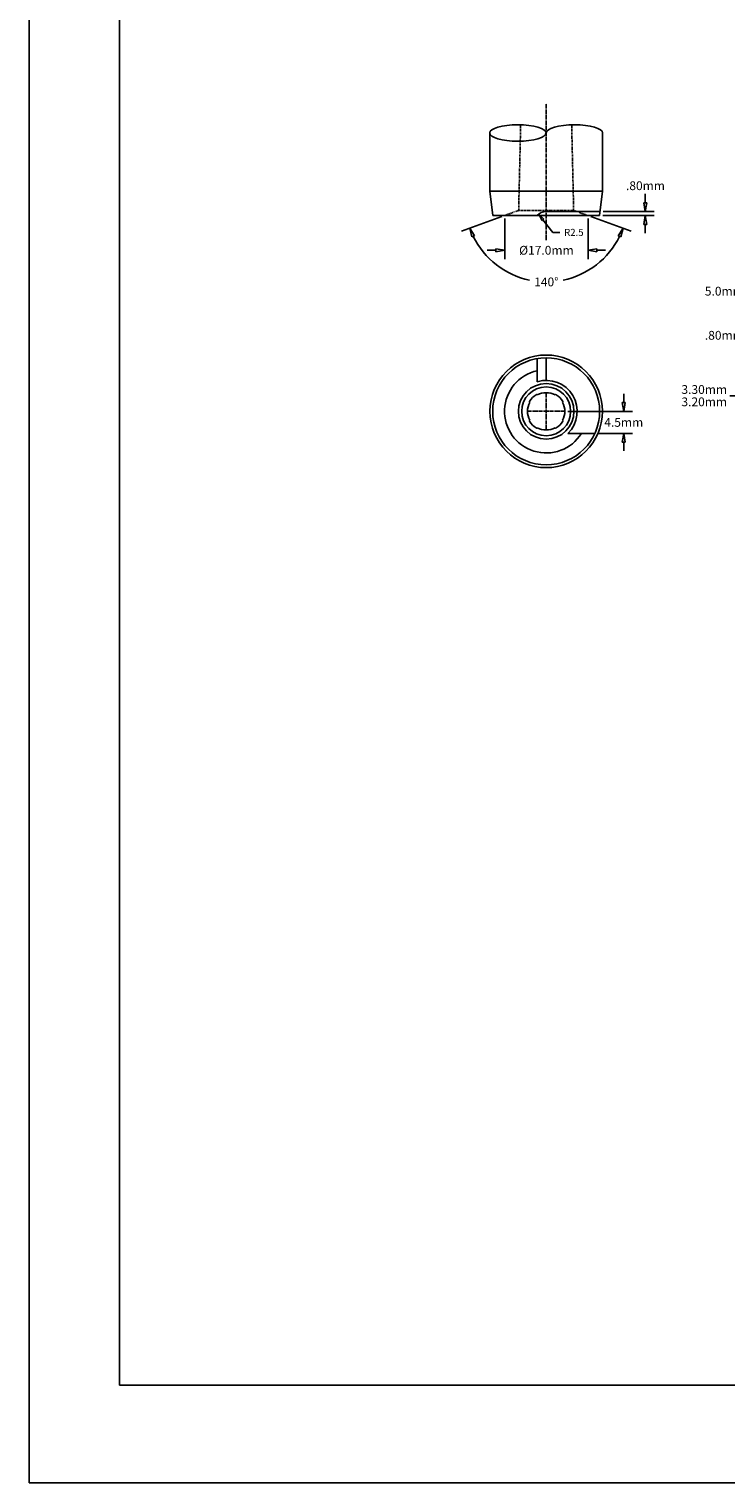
# Model space of a CAD drawing. Units: inches. Extents: x 0 to 841, y 0 to 594.
# Drawn here: x 0 to 142, y 0 to 297 of the extents above; entities that cross this region are included whole.
import ezdxf

# ---------------------------------------------------------------- set-up
doc = ezdxf.new("R2010")
doc.units = ezdxf.units.IN
doc.header["$MEASUREMENT"] = 0
doc.linetypes.add('CENTER2', pattern=[1.125, 0.75, -0.125, 0.125, -0.125])
doc.linetypes.add('HIDDEN2', pattern=[0.1875, 0.125, -0.0625])
doc.layers.add('CENTERLINE', color=1, linetype='CENTER2')
doc.layers.add('HIDDEN', color=5, linetype='HIDDEN2')
doc.dimstyles.get("Standard").update_dxf_attribs({"dimscale": 10, "dimtxt": 0.18, "dimasz": 0.18, "dimexe": 0.18, "dimexo": 0.0625, "dimgap": 0.09, "dimtad": 0, "dimtih": 1, "dimtoh": 1, "dimdec": 4, "dimzin": 0, "dimdsep": 46, "dimtxsty": 'Standard', "dimblk": 'CLOSEDBLANK', "dimcen": 0.09, "dimadec": 4, "dimazin": 0, "dimtfac": 1, "dimtdec": 4, "dimtofl": 0, "dimtmove": 0, "dimatfit": 3, "dimldrblk": 'CLOSEDBLANK', "dimfxl": 0, "dimtolj": 1, "dimtzin": 0, "dimarcsym": 0})
doc.dimstyles.new('Standard$0', dxfattribs={"dimscale": 10, "dimtxt": 0.18, "dimasz": 0.18, "dimexe": 0.18, "dimexo": 0.0625, "dimgap": 0.09, "dimtad": 0, "dimtih": 1, "dimtoh": 1, "dimdec": 4, "dimzin": 4, "dimdsep": 46, "dimtxsty": 'Standard', "dimblk": 'CLOSEDBLANK', "dimcen": 0.09, "dimadec": 5, "dimazin": 1, "dimtfac": 1, "dimtdec": 4, "dimtofl": 0, "dimtmove": 0, "dimatfit": 3, "dimldrblk": 'CLOSEDBLANK', "dimfxl": 0, "dimtolj": 1, "dimtzin": 0, "dimarcsym": 0})

# ---------------------------------------------------------------- blocks, each defined once
blk = doc.blocks.new('_ClosedBlank')
at = {"color": 0, "linetype": 'ByBlock', "lineweight": -2}
for p, q in [((-1, 0.17), (0, 0)), ((-1, 0.17), (-1, -0.17)), ((0, 0), (-1, -0.17))]:
    blk.add_line(p, q, dxfattribs=at)
blk = doc.blocks.new('*D7')
at = {"color": 0, "lineweight": -2}
for p, q in [((150, 230.46), (150, 245.26)), ((155, 231.1), (155, 245.26)), ((148.2, 243.46), (146.4, 243.46)), ((156.8, 243.46), (158.6, 243.46))]:
    blk.add_line(p, q, dxfattribs=at)
at = {"layer": 'Defpoints', "color": 0}
for p in [(155, 243.46), (150, 229.83), (155, 230.48)]:
    blk.add_point(p, dxfattribs=at)
at = {"color": 0, "lineweight": -2, "xscale": 1.8, "yscale": 1.8, "zscale": 1.8}
blk.add_blockref('_ClosedBlank', (150, 243.46), dxfattribs=at)
at = {"color": 0, "lineweight": -2, "xscale": 1.8, "yscale": 1.8, "zscale": 1.8, "rotation": 180}
blk.add_blockref('_ClosedBlank', (155, 243.46), dxfattribs=at)
at = {"color": 0, "insert": (142.05, 243.46), "char_height": 1.8, "attachment_point": 5}
blk.add_mtext('\\A1;5.0mm', dxfattribs=at)
blk = doc.blocks.new('*D23')
at = {"color": 0, "lineweight": -2}
for p, q in [((121.5, 220.71), (121.5, 222.51)), ((110.08, 218.91), (123.3, 218.91)), ((116.23, 214.41), (123.3, 214.41)), ((121.5, 212.61), (121.5, 210.81))]:
    blk.add_line(p, q, dxfattribs=at)
at = {"layer": 'Defpoints', "color": 0}
for p in [(109.46, 218.91), (121.5, 218.91), (115.6, 214.41)]:
    blk.add_point(p, dxfattribs=at)
at = {"color": 0, "lineweight": -2, "xscale": 1.8, "yscale": 1.8, "zscale": 1.8}
for p, rotation in [((121.5, 218.91), 270), ((121.5, 214.41), 90)]:
    blk.add_blockref('_ClosedBlank', p, dxfattribs=dict(at, rotation=rotation))
at = {"color": 0, "insert": (121.5, 216.66), "char_height": 1.8, "attachment_point": 5}
blk.add_mtext('\\A1;4.5mm', dxfattribs=at)
blk = doc.blocks.new('*D24')
at = {"color": 0, "lineweight": -2}
for p, q in [((106.99, 255.47), (105, 258.05)), ((108.43, 255.47), (106.99, 255.47))]:
    blk.add_line(p, q, dxfattribs=at)
at = {"layer": 'Defpoints', "color": 0}
for p in [(104.12, 259.19), (105.65, 257.21)]:
    blk.add_point(p, dxfattribs=at)
at = {"color": 0, "lineweight": -2, "xscale": 1.44, "yscale": 1.44, "zscale": 1.44, "rotation": 127.7379653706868}
blk.add_blockref('_ClosedBlank', (104.12, 259.19), dxfattribs=at)
at = {"color": 0, "insert": (111.31, 255.47), "char_height": 1.44, "attachment_point": 5}
blk.add_mtext('\\A1;R2.5', dxfattribs=at)
blk = doc.blocks.new('*D25')
at = {"color": 0, "lineweight": -2}
for p, q in [((150, 230.46), (150, 236.24)), ((150.8, 230.34), (150.8, 236.24)), ((148.2, 234.44), (146.4, 234.44)), ((152.6, 234.44), (154.4, 234.44))]:
    blk.add_line(p, q, dxfattribs=at)
at = {"layer": 'Defpoints', "color": 0}
for p in [(150.8, 234.44), (150, 229.83), (150.8, 229.71)]:
    blk.add_point(p, dxfattribs=at)
at = {"color": 0, "lineweight": -2, "xscale": 1.8, "yscale": 1.8, "zscale": 1.8}
blk.add_blockref('_ClosedBlank', (150, 234.44), dxfattribs=at)
at = {"color": 0, "lineweight": -2, "xscale": 1.8, "yscale": 1.8, "zscale": 1.8, "rotation": 180}
blk.add_blockref('_ClosedBlank', (150.8, 234.44), dxfattribs=at)
at = {"color": 0, "insert": (142.05, 234.44), "char_height": 1.8, "attachment_point": 5}
blk.add_mtext('\\A1;.80mm', dxfattribs=at)
blk = doc.blocks.new('*D32')
at = {"color": 0, "lineweight": -2}
for p, q in [((96.61, 258.7), (88.36, 255.69)), ((114.79, 258.7), (123.04, 255.69))]:
    blk.add_line(p, q, dxfattribs=at)
for start, end in [(206.197, 258.0416), (281.9584, 333.803)]:
    blk.add_arc((105.7, 262), 16.65, start, end, dxfattribs=at)
at = {"layer": 'Defpoints', "color": 0}
for p in [(97.2, 258.91), (100.03, 259.94), (111.37, 259.94), (114.2, 258.91), (99.1, 246.72)]:
    blk.add_point(p, dxfattribs=at)
at = {"color": 0, "lineweight": -2, "xscale": 1.8, "yscale": 1.8, "zscale": 1.8}
for p, rotation in [((90.05, 256.31), 113.0985010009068), ((121.35, 256.31), 66.90149899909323)]:
    blk.add_blockref('_ClosedBlank', p, dxfattribs=dict(at, rotation=rotation))
at = {"color": 0, "insert": (105.7, 245.35), "char_height": 1.8, "attachment_point": 5}
blk.add_mtext('\\A1;140°', dxfattribs=at)
blk = doc.blocks.new('*D33')
at = {"color": 0, "lineweight": -2}
for p, q in [((97.2, 258.29), (97.2, 250.01)), ((114.2, 258.29), (114.2, 250.01)), ((95.4, 251.81), (93.6, 251.81)), ((116, 251.81), (117.8, 251.81))]:
    blk.add_line(p, q, dxfattribs=at)
at = {"layer": 'Defpoints', "color": 0}
for p in [(97.2, 258.91), (114.2, 258.91), (114.2, 251.81)]:
    blk.add_point(p, dxfattribs=at)
at = {"color": 0, "lineweight": -2, "xscale": 1.8, "yscale": 1.8, "zscale": 1.8}
blk.add_blockref('_ClosedBlank', (97.2, 251.81), dxfattribs=at)
at = {"color": 0, "lineweight": -2, "xscale": 1.8, "yscale": 1.8, "zscale": 1.8, "rotation": 180}
blk.add_blockref('_ClosedBlank', (114.2, 251.81), dxfattribs=at)
at = {"color": 0, "insert": (105.7, 251.81), "char_height": 1.8, "attachment_point": 5}
blk.add_mtext('\\A1;%%C17.0mm', dxfattribs=at)
blk = doc.blocks.new('*D34')
at = {"color": 0, "lineweight": -2}
for p, q in [((150, 229.21), (150, 220.31)), ((146.8, 220.04), (146.8, 223.91)), ((145, 222.11), (143.2, 222.11)), ((151.8, 222.11), (153.6, 222.11))]:
    blk.add_line(p, q, dxfattribs=at)
at = {"layer": 'Defpoints', "color": 0}
for p in [(150, 229.83), (150, 222.11), (146.8, 219.41)]:
    blk.add_point(p, dxfattribs=at)
at = {"color": 0, "lineweight": -2, "xscale": 1.8, "yscale": 1.8, "zscale": 1.8}
blk.add_blockref('_ClosedBlank', (146.8, 222.11), dxfattribs=at)
at = {"color": 0, "lineweight": -2, "xscale": 1.8, "yscale": 1.8, "zscale": 1.8, "rotation": 180}
blk.add_blockref('_ClosedBlank', (150, 222.11), dxfattribs=at)
at = {"color": 0, "insert": (137.95, 222.11), "char_height": 1.8, "attachment_point": 5}
blk.add_mtext('\\A1;\\S3.30mm^ 3.20mm;', dxfattribs=at)
blk = doc.blocks.new('*D35')
at = {"color": 0, "lineweight": -2}
for p, q in [((125.91, 261.51), (125.91, 263.31)), ((117.2, 258.91), (127.71, 258.91)), ((117.29, 259.71), (127.71, 259.71)), ((125.91, 257.11), (125.91, 255.31))]:
    blk.add_line(p, q, dxfattribs=at)
at = {"layer": 'Defpoints', "color": 0}
for p in [(116.57, 258.91), (116.67, 259.71), (125.91, 259.71)]:
    blk.add_point(p, dxfattribs=at)
at = {"color": 0, "lineweight": -2, "xscale": 1.8, "yscale": 1.8, "zscale": 1.8}
for p, rotation in [((125.91, 259.71), 270), ((125.91, 258.91), 90)]:
    blk.add_blockref('_ClosedBlank', p, dxfattribs=dict(at, rotation=rotation))
at = {"color": 0, "insert": (125.94, 265), "char_height": 1.8, "attachment_point": 5}
blk.add_mtext('\\A1;.80mm', dxfattribs=at)

msp = doc.modelspace()

# ---------------------------------------------------------------- linework, layer by layer
for p, q in [((94.11497, 263.9106), (94.11497, 275.77746)), ((117.18497, 263.9106), (117.18497, 275.77746)), ((117.18497, 263.9106), (94.11497, 263.9106)), ((94.72889, 258.9106), (94.11497, 263.9106)), ((116.57104, 258.9106), (117.18497, 263.9106)), ((116.57104, 258.9106), (94.72889, 258.9106)), ((116.66927, 259.7106), (105.64997, 259.7106)), ((103.81693, 224.97022), (103.81693, 229.67919)), ((105.64997, 225.2414), (105.64997, 229.8317)), ((110.10294, 214.4106), (115.60087, 214.4106))]:
    msp.add_line(p, q)
for points in [[(0, 0), (841, 0), (841, 594), (0, 594)], [(18.5, 20), (822.5, 20), (822.5, 574), (18.5, 574)]]:
    msp.add_lwpolyline(points, close=True)
for radius in [11.5, 10.92349, 5.67115, 5]:
    msp.add_circle((105.64997, 218.9106), radius)
for centre, radius, start, end in [((105.64997, 257.2106), 2.5, 90, 137.156357), ((105.64997, 218.9106), 8.5, 102.4537006, 328.0342812), ((105.64997, 218.9106), 6.3308, 314.6990904, 106.8305173)]:
    msp.add_arc(centre, radius, start, end)
at = {"ltscale": 0.25}
for centre, radius, start, end in [((105.64997, 218.9106), 3.81, 151.3407406, 208.6592594), ((102.3825, 220.87014), 0.1524, 149.0482979, 240.1945192), ((105.64997, 218.9106), 3.9624, 120.9517021, 149.0482979), ((103.69042, 222.17806), 0.1524, 29.8054808, 120.9517021), ((105.64997, 218.9106), 3.81, 61.3407406, 118.6592594), ((107.60951, 222.17806), 0.1524, 59.0482979, 150.1945192), ((105.64997, 218.9106), 3.9624, 30.9517021, 59.0482979), ((108.91743, 220.87014), 0.1524, 299.8054808, 30.9517021), ((105.64997, 218.9106), 3.81, 331.3407406, 28.6592594), ((102.3825, 216.95106), 0.1524, 119.8054808, 210.9517021), ((105.64997, 218.9106), 3.9624, 210.9517021, 239.0482979), ((105.64997, 218.9106), 3.9624, 300.9517021, 329.0482979), ((108.91743, 216.95106), 0.1524, 329.0482979, 60.1945192), ((103.69042, 215.64314), 0.1524, 239.0482979, 330.1945192), ((105.64997, 218.9106), 3.81, 241.3407406, 298.6592594), ((107.60951, 215.64314), 0.1524, 209.8054808, 300.9517021)]:
    msp.add_arc(centre, radius, start, end, dxfattribs=at)
msp.add_ellipse((99.88247, 275.77746), major_axis=(-5.7675, 0), ratio=0.291449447)
msp.add_ellipse((111.41747, 275.77746), major_axis=(-5.7675, 0), ratio=0.291449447, start_param=3.141592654, end_param=6.283185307)
at = {"layer": 'CENTERLINE'}
for p, q in [((105.64997, 253.9106), (105.64997, 281.80785)), ((105.64997, 215.1006), (105.64997, 222.7206)), ((101.83997, 218.9106), (109.45997, 218.9106))]:
    msp.add_line(p, q, dxfattribs=at)
at = {"layer": 'HIDDEN'}
for p, q in [((100.02852, 259.94021), (100.43902, 277.45055)), ((111.27141, 259.94021), (110.86091, 277.45055)), ((99.97879, 259.94021), (97.14997, 258.9106)), ((111.32114, 259.94021), (99.97879, 259.94021)), ((111.32114, 259.94021), (114.14997, 258.9106))]:
    msp.add_line(p, q, dxfattribs=at)

# ---------------------------------------------------------------- dimensions: what is measured, and where the dimension line sits
dim = msp.add_linear_dim(base=(125.90624, 259.7106), p1=(116.57104, 258.9106), p2=(116.66927, 259.7106), angle=90, dimstyle='Standard$0', override={"dimdec": 2, "dimpost": 'mm', "dimblk1": 'ClosedBlank', "dimblk2": 'ClosedBlank', "dimsah": 1, "dimtmove": 2})
dim.commit()
dim.dimension.update_dxf_attribs({"geometry": '*D35', "text_midpoint": (125.94037, 265.00227), "dimtype": 160})
dim = msp.add_angular_dim_2l(base=(99.1048, 246.71566), line1=((111.37087, 259.94021), (114.1997, 258.9106)), line2=((100.02852, 259.94021), (97.1997, 258.9106)), dimstyle='Standard', override={"dimadec": 0})
dim.commit()
dim.dimension.update_dxf_attribs({"geometry": '*D32', "text_midpoint": (105.6997, 245.35392)})
dim = msp.add_linear_dim(base=(114.1997, 251.81332), p1=(97.1997, 258.9106), p2=(114.1997, 258.9106), text='%%C<>', dimstyle='Standard$0', override={"dimdec": 1, "dimpost": 'mm'})
dim.commit()
dim.dimension.update_dxf_attribs({"geometry": '*D33', "text_midpoint": (105.6997, 251.81332)})
dim = msp.add_radius_dim(center=(105.64997, 257.2106), mpoint=(104.11984, 259.18764), dimstyle='Standard', override={"dimscale": 8, "dimdec": 1, "dimtmove": 1})
dim.commit()
dim.dimension.update_dxf_attribs({"geometry": '*D24', "text_midpoint": (106.99376, 255.47431), "dimtype": 164})
for base, p1, p2, override, picture, middle in [((154.99997, 243.46019), (149.99997, 229.83168), (154.99997, 230.4756), {"dimscale": 10, "dimdec": 1, "dimpost": 'mm', "dimblk1": 'ClosedBlank', "dimblk2": 'ClosedBlank', "dimsah": 1}, '*D7', (142.04997, 243.46019)), ((150.79997, 234.4356), (149.99997, 229.83168), (150.79997, 229.71386), {"dimscale": 10, "dimdec": 2, "dimpost": 'mm', "dimblk1": 'ClosedBlank', "dimblk2": 'ClosedBlank', "dimsah": 1}, '*D25', (142.04997, 234.4356)), ((149.99997, 222.11187), (146.79997, 219.4106), (149.99997, 229.83168), {"dimgap": 0.09, "dimdec": 2, "dimpost": 'mm', "dimtol": 0, "dimlim": 1, "dimtp": 0.1, "dimtm": 1e-09, "dimtdec": 2}, '*D34', (137.94997, 222.11187))]:
    dim = msp.add_linear_dim(base=base, p1=p1, p2=p2, dimstyle='Standard$0', override=override)
    dim.commit()
    dim.dimension.update_dxf_attribs({"geometry": picture, "text_midpoint": middle, "dimtype": 160})
dim = msp.add_linear_dim(base=(121.49722, 218.9106), p1=(115.60087, 214.4106), p2=(109.45997, 218.9106), angle=90, dimstyle='Standard$0', override={"dimdec": 1, "dimpost": 'mm'})
dim.commit()
dim.dimension.update_dxf_attribs({"geometry": '*D23', "text_midpoint": (121.49722, 216.6606)})

doc.saveas('drawing.dxf')
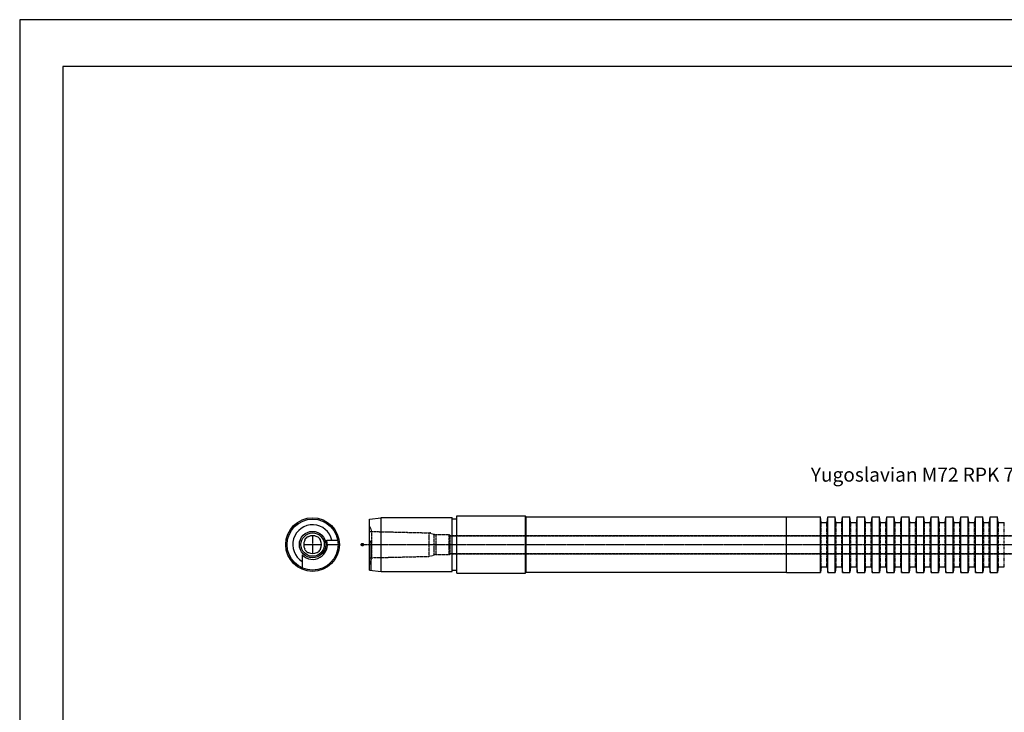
# Model space of a CAD drawing. Units: inches. Extents: x 0 to 841, y 0 to 594.
# Drawn here: x 0 to 422, y 297 to 594 of the extents above; entities that cross this region are included whole.
import ezdxf
from ezdxf.enums import TextEntityAlignment as Align

# ---------------------------------------------------------------- set-up
doc = ezdxf.new("R2010")
doc.units = ezdxf.units.IN
doc.header["$MEASUREMENT"] = 0
for name, pattern in [('CENTER2', [1.125, 0.75, -0.125, 0.125, -0.125]), ('HIDDEN2', [0.1875, 0.125, -0.0625]), ('PHANTOM', [2.5, 1.25, -0.25, 0.25, -0.25, 0.25, -0.25])]:
    doc.linetypes.add(name, pattern=pattern)
for name, color, linetype in [('CENTER', 1, 'CENTER2'), ('CENTERLINE', 1, 'CENTER2'), ('HIDDEN', 5, 'HIDDEN2'), ('PHANTOM', 252, 'PHANTOM')]:
    doc.layers.add(name, color=color, linetype=linetype)

msp = doc.modelspace()

# ---------------------------------------------------------------- hatches: boundary and pattern name
at = {"layer": 'CENTER'}
h = msp.add_hatch(dxfattribs=at)
h.set_pattern_fill('ANSI31', color=256, style=0)
h.set_pattern_definition([(45, (98, 318.91057), (-0.08838835, 0.08838835), [])])
h.paths.add_polyline_path([(146.99997, 369.4106, 0.414213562), (146.49997, 368.9106), (146.99997, 368.9106)])
h.paths.add_polyline_path([(147.49997, 368.9106), (146.99997, 368.9106), (146.99997, 368.4106, 0.414213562)])

# ---------------------------------------------------------------- linework, layer by layer
for p, q in [((149.99997, 379.83168), (154.99997, 380.4456)), ((149.99997, 379.83168), (154.99997, 380.4456)), ((154.99997, 380.4756), (185.49997, 380.4756)), ((154.99997, 357.3456), (154.99997, 380.4756)), ((185.49997, 357.3456), (185.49997, 380.4756)), ((187.49997, 356.6356), (187.49997, 381.1856)), ((187.49997, 381.1856), (216.99997, 381.1856)), ((216.99997, 356.6356), (216.99997, 381.1856)), ((217.24997, 357.0106), (217.24997, 380.8106)), ((217.24997, 380.7606), (328.99997, 380.7606)), ((328.99997, 380.8106), (343.49997, 380.8106)), ((328.99997, 357.0106), (328.99997, 380.8106)), ((343.49997, 357.0106), (343.49997, 380.8106)), ((343.78387, 378.49841), (343.49997, 380.8106)), ((346.38273, 378.49841), (346.66663, 380.8106)), ((346.66663, 357.0106), (346.66663, 380.8106)), ((346.66663, 380.8106), (349.8333, 380.8106)), ((349.8333, 357.0106), (349.8333, 380.8106)), ((350.1172, 378.49841), (349.8333, 380.8106)), ((352.71606, 378.49841), (352.99997, 380.8106)), ((352.99997, 357.0106), (352.99997, 380.8106)), ((352.99997, 380.8106), (356.16663, 380.8106)), ((356.16663, 357.0106), (356.16663, 380.8106)), ((356.45053, 378.49841), (356.16663, 380.8106)), ((359.0494, 378.49841), (359.3333, 380.8106)), ((359.3333, 357.0106), (359.3333, 380.8106)), ((359.3333, 380.8106), (362.49997, 380.8106)), ((362.49997, 357.0106), (362.49997, 380.8106)), ((362.78387, 378.49841), (362.49997, 380.8106)), ((365.38273, 378.49841), (365.66663, 380.8106)), ((365.66663, 357.0106), (365.66663, 380.8106)), ((365.66663, 380.8106), (368.8333, 380.8106)), ((368.8333, 357.0106), (368.8333, 380.8106)), ((369.1172, 378.49841), (368.8333, 380.8106)), ((371.71606, 378.49841), (371.99997, 380.8106)), ((371.99997, 357.0106), (371.99997, 380.8106)), ((371.99997, 380.8106), (375.16663, 380.8106)), ((375.16663, 357.0106), (375.16663, 380.8106)), ((375.45053, 378.49841), (375.16663, 380.8106)), ((378.0494, 378.49841), (378.3333, 380.8106)), ((378.3333, 357.0106), (378.3333, 380.8106)), ((378.3333, 380.8106), (381.49997, 380.8106)), ((381.49997, 357.0106), (381.49997, 380.8106)), ((381.78387, 378.49841), (381.49997, 380.8106)), ((384.38273, 378.49841), (384.66663, 380.8106)), ((384.66663, 357.0106), (384.66663, 380.8106)), ((384.66663, 380.8106), (387.8333, 380.8106)), ((387.8333, 357.0106), (387.8333, 380.8106)), ((388.1172, 378.49841), (387.8333, 380.8106)), ((390.71606, 378.49841), (390.99997, 380.8106)), ((390.99997, 357.0106), (390.99997, 380.8106)), ((390.99997, 380.8106), (394.16663, 380.8106)), ((394.16663, 357.0106), (394.16663, 380.8106)), ((394.45053, 378.49841), (394.16663, 380.8106)), ((397.0494, 378.49841), (397.3333, 380.8106)), ((397.3333, 357.0106), (397.3333, 380.8106)), ((397.3333, 380.8106), (400.49997, 380.8106)), ((400.49997, 357.0106), (400.49997, 380.8106)), ((400.78387, 378.49841), (400.49997, 380.8106)), ((403.38273, 378.49841), (403.66663, 380.8106)), ((403.66663, 357.0106), (403.66663, 380.8106)), ((403.66663, 380.8106), (406.8333, 380.8106)), ((406.8333, 357.0106), (406.8333, 380.8106)), ((407.1172, 378.49841), (406.8333, 380.8106)), ((409.71606, 378.49841), (409.99997, 380.8106)), ((409.99997, 357.0106), (409.99997, 380.8106)), ((409.99997, 380.8106), (413.16663, 380.8106)), ((413.16663, 357.0106), (413.16663, 380.8106)), ((413.45053, 378.49841), (413.16663, 380.8106)), ((416.0494, 378.49841), (416.3333, 380.8106)), ((416.3333, 357.0106), (416.3333, 380.8106)), ((416.3333, 380.8106), (419.49997, 380.8106)), ((419.49997, 357.0106), (419.49997, 380.8106)), ((419.78387, 378.49841), (419.49997, 380.8106)), ((149.99997, 357.98952), (149.99997, 379.83168)), ((185.49997, 379.9106), (187.49997, 379.9106)), ((343.88312, 378.4106), (346.28348, 378.4106)), ((350.21645, 378.4106), (352.61681, 378.4106)), ((356.54979, 378.4106), (358.95014, 378.4106)), ((362.88312, 378.4106), (365.28348, 378.4106)), ((369.21645, 378.4106), (371.61681, 378.4106)), ((375.54979, 378.4106), (377.95014, 378.4106)), ((381.88312, 378.4106), (384.28348, 378.4106)), ((388.21645, 378.4106), (390.70014, 378.4106)), ((394.54979, 378.4106), (396.95014, 378.4106)), ((400.88312, 378.4106), (403.36681, 378.4106)), ((407.21645, 378.4106), (409.61681, 378.4106)), ((413.54979, 378.4106), (415.95014, 378.4106)), ((419.88312, 378.4106), (422.28348, 378.4106)), ((131.70959, 370.74363), (136.41856, 370.74363)), ((131.98077, 368.9106), (136.57107, 368.9106)), ((150.79997, 357.89129), (150.79997, 368.9106)), ((121.14997, 364.45762), (121.14997, 358.95969)), ((343.78387, 359.32279), (343.49997, 357.0106)), ((343.88312, 359.4106), (346.28348, 359.4106)), ((346.38273, 359.32279), (346.66663, 357.0106)), ((350.1172, 359.32279), (349.8333, 357.0106)), ((350.13312, 359.4106), (352.61681, 359.4106)), ((352.71606, 359.32279), (352.99997, 357.0106)), ((356.45053, 359.32279), (356.16663, 357.0106)), ((356.54979, 359.4106), (358.95014, 359.4106)), ((359.0494, 359.32279), (359.3333, 357.0106)), ((362.78387, 359.32279), (362.49997, 357.0106)), ((362.88312, 359.4106), (365.28348, 359.4106)), ((365.38273, 359.32279), (365.66663, 357.0106)), ((369.1172, 359.32279), (368.8333, 357.0106)), ((369.21645, 359.4106), (371.61681, 359.4106)), ((371.71606, 359.32279), (371.99997, 357.0106)), ((375.45053, 359.32279), (375.16663, 357.0106)), ((375.54979, 359.4106), (377.95014, 359.4106)), ((378.0494, 359.32279), (378.3333, 357.0106)), ((381.78387, 359.32279), (381.49997, 357.0106)), ((381.88312, 359.4106), (384.28348, 359.4106)), ((384.38273, 359.32279), (384.66663, 357.0106)), ((388.1172, 359.32279), (387.8333, 357.0106)), ((388.21645, 359.4106), (390.70014, 359.4106)), ((390.71606, 359.32279), (390.99997, 357.0106)), ((394.45053, 359.32279), (394.16663, 357.0106)), ((394.54979, 359.4106), (396.95014, 359.4106)), ((397.0494, 359.32279), (397.3333, 357.0106)), ((400.78387, 359.32279), (400.49997, 357.0106)), ((400.88312, 359.4106), (403.36681, 359.4106)), ((403.38273, 359.32279), (403.66663, 357.0106)), ((407.1172, 359.32279), (406.8333, 357.0106)), ((407.21645, 359.4106), (409.61681, 359.4106)), ((409.71606, 359.32279), (409.99997, 357.0106)), ((413.45053, 359.32279), (413.16663, 357.0106)), ((413.54979, 359.4106), (415.95014, 359.4106)), ((416.0494, 359.32279), (416.3333, 357.0106)), ((419.78387, 359.32279), (419.49997, 357.0106)), ((419.88312, 359.4106), (422.28348, 359.4106)), ((149.99997, 357.98952), (154.99997, 357.3756)), ((149.99997, 357.98952), (154.99997, 357.3756)), ((154.99997, 357.3456), (185.49997, 357.3456)), ((185.49997, 357.9106), (187.49997, 357.9106)), ((187.49997, 356.6356), (216.99997, 356.6356)), ((217.24997, 357.0606), (328.99997, 357.0606)), ((328.99997, 357.0106), (343.49997, 357.0106)), ((346.66663, 357.0106), (349.8333, 357.0106)), ((352.99997, 357.0106), (356.16663, 357.0106)), ((359.3333, 357.0106), (362.49997, 357.0106)), ((365.66663, 357.0106), (368.8333, 357.0106)), ((371.99997, 357.0106), (375.16663, 357.0106)), ((378.3333, 357.0106), (381.49997, 357.0106)), ((384.66663, 357.0106), (387.8333, 357.0106)), ((390.99997, 357.0106), (394.16663, 357.0106)), ((397.3333, 357.0106), (400.49997, 357.0106)), ((403.66663, 357.0106), (406.8333, 357.0106)), ((409.99997, 357.0106), (413.16663, 357.0106)), ((416.3333, 357.0106), (419.49997, 357.0106))]:
    msp.add_line(p, q)
for points in [[(0, 0), (841, 0), (841, 594), (0, 594)], [(18.5, 20), (822.5, 20), (822.5, 574), (18.5, 574)]]:
    msp.add_lwpolyline(points, close=True)
for radius in [11.5, 10.92349, 5.67115, 5]:
    msp.add_circle((125.64997, 368.9106), radius)
for centre, radius, start, end in [((217.24997, 381.0606), 0.25, 180, 270), ((125.64997, 368.9106), 8.5, 12.4537006, 238.0342812), ((343.88312, 378.5106), 0.1, 187, 270), ((346.28348, 378.5106), 0.1, 270, 353), ((350.21645, 378.5106), 0.1, 187, 270), ((352.61681, 378.5106), 0.1, 270, 353), ((356.54979, 378.5106), 0.1, 187, 270), ((358.95014, 378.5106), 0.1, 270, 353), ((362.88312, 378.5106), 0.1, 187, 270), ((365.28348, 378.5106), 0.1, 270, 353), ((369.21645, 378.5106), 0.1, 187, 270), ((371.61681, 378.5106), 0.1, 270, 353), ((375.54979, 378.5106), 0.1, 187, 270), ((377.95014, 378.5106), 0.1, 270, 353), ((381.88312, 378.5106), 0.1, 187, 270), ((384.28348, 378.5106), 0.1, 270, 353), ((388.21645, 378.5106), 0.1, 187, 270), ((390.61681, 378.5106), 0.1, 270, 353), ((394.54979, 378.5106), 0.1, 187, 270), ((396.95014, 378.5106), 0.1, 270, 353), ((400.88312, 378.5106), 0.1, 187, 270), ((403.28348, 378.5106), 0.1, 270, 353), ((407.21645, 378.5106), 0.1, 187, 270), ((409.61681, 378.5106), 0.1, 270, 353), ((413.54979, 378.5106), 0.1, 187, 270), ((415.95014, 378.5106), 0.1, 270, 353), ((419.88312, 378.5106), 0.1, 187, 270), ((422.28348, 378.5106), 0.1, 270, 353), ((125.64997, 368.9106), 6.3308, 224.6990904, 16.8305173), ((148.29997, 368.9106), 2.5, 0, 47.156357), ((343.88312, 359.3106), 0.1, 90, 173), ((346.28348, 359.3106), 0.1, 7, 90), ((350.21645, 359.3106), 0.1, 90, 173), ((352.61681, 359.3106), 0.1, 7, 90), ((356.54979, 359.3106), 0.1, 90, 173), ((358.95014, 359.3106), 0.1, 7, 90), ((362.88312, 359.3106), 0.1, 90, 173), ((365.28348, 359.3106), 0.1, 7, 90), ((369.21645, 359.3106), 0.1, 90, 173), ((371.61681, 359.3106), 0.1, 7, 90), ((375.54979, 359.3106), 0.1, 90, 173), ((377.95014, 359.3106), 0.1, 7, 90), ((381.88312, 359.3106), 0.1, 90, 173), ((384.28348, 359.3106), 0.1, 7, 90), ((388.21645, 359.3106), 0.1, 90, 173), ((390.61681, 359.3106), 0.1, 7, 90), ((394.54979, 359.3106), 0.1, 90, 173), ((396.95014, 359.3106), 0.1, 7, 90), ((400.88312, 359.3106), 0.1, 90, 173), ((403.28348, 359.3106), 0.1, 7, 90), ((407.21645, 359.3106), 0.1, 90, 173), ((409.61681, 359.3106), 0.1, 7, 90), ((413.54979, 359.3106), 0.1, 90, 173), ((415.95014, 359.3106), 0.1, 7, 90), ((419.88312, 359.3106), 0.1, 90, 173), ((422.28348, 359.3106), 0.1, 7, 90), ((217.24997, 356.7606), 0.25, 90, 180)]:
    msp.add_arc(centre, radius, start, end)
at = {"ltscale": 0.25}
for centre, radius, start, end in [((125.64997, 368.9106), 3.9624, 120.9517021, 149.0482979), ((123.69042, 372.17806), 0.1524, 29.8054808, 120.9517021), ((125.64997, 368.9106), 3.81, 61.3407406, 118.6592594), ((127.60951, 372.17806), 0.1524, 59.0482979, 150.1945192), ((125.64997, 368.9106), 3.9624, 30.9517021, 59.0482979), ((125.64997, 368.9106), 3.81, 151.3407406, 208.6592594), ((122.3825, 370.87014), 0.1524, 149.0482979, 240.1945192), ((128.91743, 370.87014), 0.1524, 299.8054808, 30.9517021), ((125.64997, 368.9106), 3.81, 331.3407406, 28.6592594), ((122.3825, 366.95106), 0.1524, 119.8054808, 210.9517021), ((125.64997, 368.9106), 3.9624, 210.9517021, 239.0482979), ((123.69042, 365.64314), 0.1524, 239.0482979, 330.1945192), ((125.64997, 368.9106), 3.81, 241.3407406, 298.6592594), ((127.60951, 365.64314), 0.1524, 209.8054808, 300.9517021), ((125.64997, 368.9106), 3.9624, 300.9517021, 329.0482979), ((128.91743, 366.95106), 0.1524, 329.0482979, 60.1945192)]:
    msp.add_arc(centre, radius, start, end, dxfattribs=at)
at = {"layer": 'CENTER'}
msp.add_line((146.99997, 368.4106), (146.99997, 369.4106), dxfattribs=at)
msp.add_circle((146.99997, 368.9106), 0.5, dxfattribs=at)
at = {"layer": 'CENTERLINE'}
for p, q in [((125.64997, 372.7206), (125.64997, 365.1006)), ((121.83997, 368.9106), (129.45997, 368.9106)), ((146.99997, 368.9106), (694.49997, 368.9106))]:
    msp.add_line(p, q, dxfattribs=at)
at = {"layer": 'HIDDEN'}
for p, q in [((151.02957, 374.58177), (149.99997, 377.4106)), ((149.99997, 374.55618), (175.66907, 373.95441)), ((151.02957, 363.23943), (151.02957, 374.58177)), ((175.66907, 363.86672), (175.66907, 373.95441)), ((175.66907, 373.95441), (177.78483, 373.33238)), ((177.78483, 364.48875), (177.78483, 373.33238)), ((178.63102, 373.21057), (184.24493, 373.21057)), ((178.63102, 364.61057), (178.63102, 373.21057)), ((184.24493, 364.61057), (184.24493, 373.21057)), ((184.24493, 373.21057), (184.7349, 372.7206)), ((184.5825, 372.873), (690.76572, 372.873)), ((184.7349, 372.7206), (689.99997, 372.7206)), ((184.73497, 365.1006), (184.73497, 372.7206)), ((149.99997, 363.26502), (175.66907, 363.86679)), ((175.66907, 363.86672), (177.78483, 364.48875)), ((178.63102, 364.61057), (184.24493, 364.61057)), ((184.24493, 364.61057), (184.73497, 365.1006)), ((184.58257, 364.9482), (690.76572, 364.9482)), ((184.73497, 365.1006), (689.99997, 365.1006)), ((151.02957, 363.23943), (149.99997, 360.4106))]:
    msp.add_line(p, q, dxfattribs=at)
for centre, start, end in [((178.63102, 376.21057), 253.6167, 270), ((178.63102, 361.61057), 90, 106.3833)]:
    msp.add_arc(centre, 3, start, end, dxfattribs=at)
msp.add_point((176.04493, 373.9456), dxfattribs=at)
at = {"layer": 'PHANTOM'}
for p, q in [((343.78387, 359.32279), (343.78387, 378.49841)), ((343.88312, 359.4106), (343.88312, 378.4106)), ((346.28348, 359.4106), (346.28348, 378.4106)), ((346.38273, 359.32279), (346.38273, 378.49841)), ((350.1172, 359.32279), (350.1172, 378.49841)), ((350.21645, 359.4106), (350.21645, 378.4106)), ((352.61681, 359.4106), (352.61681, 378.4106)), ((352.71606, 359.32279), (352.71606, 378.49841)), ((356.45053, 359.32279), (356.45053, 378.49841)), ((356.54979, 359.4106), (356.54979, 378.4106)), ((358.95014, 359.4106), (358.95014, 378.4106)), ((359.0494, 359.32279), (359.0494, 378.49841)), ((362.78387, 359.32279), (362.78387, 378.49841)), ((362.88312, 359.4106), (362.88312, 378.4106)), ((365.28348, 359.4106), (365.28348, 378.4106)), ((365.38273, 359.32279), (365.38273, 378.49841)), ((369.1172, 359.32279), (369.1172, 378.49841)), ((369.21645, 359.4106), (369.21645, 378.4106)), ((371.61681, 359.4106), (371.61681, 378.4106)), ((371.71606, 359.32279), (371.71606, 378.49841)), ((375.45053, 359.32279), (375.45053, 378.49841)), ((375.54979, 359.4106), (375.54979, 378.4106)), ((377.95014, 359.4106), (377.95014, 378.4106)), ((378.0494, 359.32279), (378.0494, 378.49841)), ((381.78387, 359.32279), (381.78387, 378.49841)), ((381.88312, 359.4106), (381.88312, 378.4106)), ((384.28348, 359.4106), (384.28348, 378.4106)), ((384.38273, 359.32279), (384.38273, 378.49841)), ((388.1172, 359.32279), (388.1172, 378.49841)), ((388.21645, 359.4106), (388.21645, 378.4106)), ((390.61681, 359.4106), (390.61681, 378.4106)), ((390.71606, 359.32279), (390.71606, 378.49841)), ((394.45053, 359.32279), (394.45053, 378.49841)), ((394.54979, 359.4106), (394.54979, 378.4106)), ((396.95014, 359.4106), (396.95014, 378.4106)), ((397.0494, 359.32279), (397.0494, 378.49841)), ((400.78387, 359.32279), (400.78387, 378.49841)), ((400.88312, 359.4106), (400.88312, 378.4106)), ((403.28348, 359.4106), (403.28348, 378.4106)), ((403.38273, 359.32279), (403.38273, 378.49841)), ((407.1172, 359.32279), (407.1172, 378.49841)), ((407.21645, 359.4106), (407.21645, 378.4106)), ((409.61681, 359.4106), (409.61681, 378.4106)), ((409.71606, 359.32279), (409.71606, 378.49841)), ((413.45053, 359.32279), (413.45053, 378.49841)), ((413.54979, 359.4106), (413.54979, 378.4106)), ((415.95014, 359.4106), (415.95014, 378.4106)), ((416.0494, 359.32279), (416.0494, 378.49841)), ((419.78387, 359.32279), (419.78387, 378.49841)), ((419.88312, 359.4106), (419.88312, 378.4106)), ((422.28348, 359.4106), (422.28348, 378.4106))]:
    msp.add_line(p, q, dxfattribs=at)

# ---------------------------------------------------------------- texts
msp.add_text('Yugoslavian M72 RPK 7,62 x 39,0', height=6).set_placement((400.5, 398.91057), align=Align.MIDDLE_CENTER)

doc.saveas('drawing.dxf')
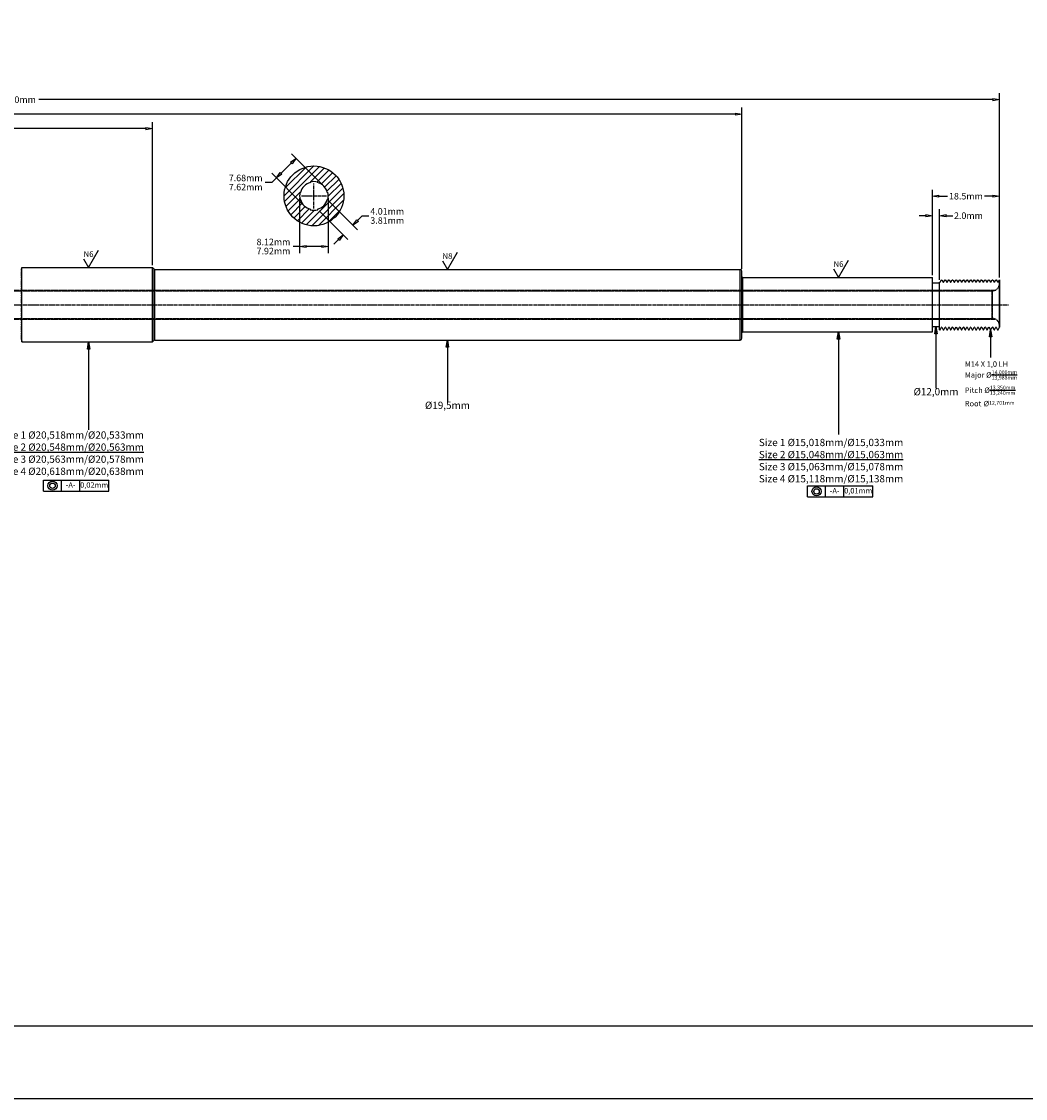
# Model space of a CAD drawing. Units: inches. Extents: x 0 to 841, y 0 to 594.
# Drawn here: x 422 to 699, y 0 to 297 of the extents above; entities that cross this region are included whole.
import ezdxf
from ezdxf.enums import TextEntityAlignment as Align

# ---------------------------------------------------------------- set-up
doc = ezdxf.new("R2010")
doc.units = ezdxf.units.IN
doc.header["$MEASUREMENT"] = 0
for name, pattern in [('CENTER2', [1.125, 0.75, -0.125, 0.125, -0.125]), ('HIDDEN2', [0.1875, 0.125, -0.0625]), ('PHANTOM', [2.5, 1.25, -0.25, 0.25, -0.25, 0.25, -0.25])]:
    doc.linetypes.add(name, pattern=pattern)
for name, color, linetype in [('CENTER', 1, 'CENTER2'), ('CENTERLINE', 1, 'CENTER2'), ('HATCH', 253, 'Continuous'), ('HIDDEN', 5, 'HIDDEN2'), ('PHANTOM', 252, 'PHANTOM'), ('TEXT', 5, 'Continuous')]:
    doc.layers.add(name, color=color, linetype=linetype)
doc.dimstyles.get("Standard").update_dxf_attribs({"dimscale": 10, "dimtxt": 0.18, "dimasz": 0.18, "dimexe": 0.18, "dimexo": 0.0625, "dimgap": 0.09, "dimtad": 0, "dimtih": 1, "dimtoh": 1, "dimdec": 4, "dimzin": 0, "dimdsep": 46, "dimtxsty": 'Standard', "dimblk": 'CLOSEDBLANK', "dimcen": 0.09, "dimadec": 4, "dimazin": 0, "dimtfac": 1, "dimtdec": 4, "dimtofl": 0, "dimtmove": 0, "dimatfit": 3, "dimldrblk": 'CLOSEDBLANK', "dimfxl": 0, "dimtolj": 1, "dimtzin": 0, "dimarcsym": 0})
doc.dimstyles.new('Standard$0', dxfattribs={"dimscale": 10, "dimtxt": 0.18, "dimasz": 0.18, "dimexe": 0.18, "dimexo": 0.0625, "dimgap": 0.09, "dimtad": 0, "dimtih": 1, "dimtoh": 1, "dimdec": 4, "dimzin": 4, "dimdsep": 46, "dimtxsty": 'Standard', "dimblk": 'CLOSEDBLANK', "dimcen": 0.09, "dimadec": 5, "dimazin": 1, "dimtfac": 1, "dimtdec": 4, "dimtofl": 0, "dimtmove": 0, "dimatfit": 3, "dimldrblk": 'CLOSEDBLANK', "dimfxl": 0, "dimtolj": 1, "dimtzin": 0, "dimarcsym": 0})

# ---------------------------------------------------------------- blocks, each defined once
blk = doc.blocks.new('_ClosedBlank')
at = {"color": 0, "linetype": 'ByBlock', "lineweight": -2}
for p, q in [((-1, 0.17), (0, 0)), ((-1, 0.17), (-1, -0.17)), ((0, 0), (-1, -0.17))]:
    blk.add_line(p, q, dxfattribs=at)
blk = doc.blocks.new('*D12')
at = {"color": 0, "lineweight": -2}
for p, q in [((150, 230.46), (150, 269.26)), ((151.8, 267.46), (298.09, 267.46)), ((456.67, 267.46), (310.39, 267.46)), ((458.47, 229.81), (458.47, 269.26))]:
    blk.add_line(p, q, dxfattribs=at)
at = {"layer": 'Defpoints', "color": 0}
for p in [(150, 267.46), (150, 229.83), (458.47, 229.19)]:
    blk.add_point(p, dxfattribs=at)
at = {"color": 0, "lineweight": -2, "xscale": 1.8, "yscale": 1.8, "zscale": 1.8, "rotation": 180}
blk.add_blockref('_ClosedBlank', (150, 267.46), dxfattribs=at)
at = {"color": 0, "lineweight": -2, "xscale": 1.8, "yscale": 1.8, "zscale": 1.8}
blk.add_blockref('_ClosedBlank', (458.47, 267.46), dxfattribs=at)
at = {"color": 0, "insert": (304.24, 267.46), "char_height": 1.8, "attachment_point": 5}
blk.add_mtext('\\A1;308.5mm', dxfattribs=at)
blk = doc.blocks.new('*D13')
at = {"color": 0, "lineweight": -2}
for p, q in [((150, 230.46), (150, 273.26)), ((621, 228.79), (621, 273.26)), ((151.8, 271.46), (379.65, 271.46)), ((619.2, 271.46), (391.35, 271.46))]:
    blk.add_line(p, q, dxfattribs=at)
at = {"layer": 'Defpoints', "color": 0}
for p in [(150, 271.46), (150, 229.83), (621, 228.16)]:
    blk.add_point(p, dxfattribs=at)
at = {"color": 0, "lineweight": -2, "xscale": 1.8, "yscale": 1.8, "zscale": 1.8, "rotation": 180}
blk.add_blockref('_ClosedBlank', (150, 271.46), dxfattribs=at)
at = {"color": 0, "lineweight": -2, "xscale": 1.8, "yscale": 1.8, "zscale": 1.8}
blk.add_blockref('_ClosedBlank', (621, 271.46), dxfattribs=at)
at = {"color": 0, "insert": (385.5, 271.46), "char_height": 1.8, "attachment_point": 5}
blk.add_mtext('\\A1;471.0mm', dxfattribs=at)
blk = doc.blocks.new('*D14')
at = {"color": 0, "lineweight": -2}
for p, q in [((673.5, 231.06), (673.5, 250.63)), ((692, 226.43), (692, 250.63)), ((675.3, 248.83), (677.65, 248.83)), ((690.2, 248.83), (687.85, 248.83))]:
    blk.add_line(p, q, dxfattribs=at)
at = {"layer": 'Defpoints', "color": 0}
for p in [(673.5, 248.83), (673.5, 230.44), (692, 225.8)]:
    blk.add_point(p, dxfattribs=at)
at = {"color": 0, "lineweight": -2, "xscale": 1.8, "yscale": 1.8, "zscale": 1.8, "rotation": 180}
blk.add_blockref('_ClosedBlank', (673.5, 248.83), dxfattribs=at)
at = {"color": 0, "lineweight": -2, "xscale": 1.8, "yscale": 1.8, "zscale": 1.8}
blk.add_blockref('_ClosedBlank', (692, 248.83), dxfattribs=at)
at = {"color": 0, "insert": (682.75, 248.83), "char_height": 1.8, "attachment_point": 5}
blk.add_mtext('\\A1;18.5mm', dxfattribs=at)
blk = doc.blocks.new('*D15')
at = {"color": 0, "lineweight": -2}
for p, q in [((150, 230.46), (150, 277.26)), ((692, 226.43), (692, 277.26)), ((151.8, 275.46), (414.85, 275.46)), ((690.2, 275.46), (427.15, 275.46))]:
    blk.add_line(p, q, dxfattribs=at)
at = {"layer": 'Defpoints', "color": 0}
for p in [(692, 275.46), (150, 229.83), (692, 225.8)]:
    blk.add_point(p, dxfattribs=at)
at = {"color": 0, "lineweight": -2, "xscale": 1.8, "yscale": 1.8, "zscale": 1.8, "rotation": 180}
blk.add_blockref('_ClosedBlank', (150, 275.46), dxfattribs=at)
at = {"color": 0, "lineweight": -2, "xscale": 1.8, "yscale": 1.8, "zscale": 1.8}
blk.add_blockref('_ClosedBlank', (692, 275.46), dxfattribs=at)
at = {"color": 0, "insert": (421, 275.46), "char_height": 1.8, "attachment_point": 5}
blk.add_mtext('\\A1;542.0mm', dxfattribs=at)
blk = doc.blocks.new('*D17')
at = {"color": 0, "lineweight": -2}
for p, q in [((673.5, 227.06), (673.5, 245.26)), ((675.5, 225.78), (675.5, 245.26)), ((671.7, 243.46), (669.9, 243.46)), ((677.3, 243.46), (679.1, 243.46))]:
    blk.add_line(p, q, dxfattribs=at)
at = {"layer": 'Defpoints', "color": 0}
for p in [(675.5, 243.46), (673.5, 226.44), (675.5, 225.15)]:
    blk.add_point(p, dxfattribs=at)
at = {"color": 0, "lineweight": -2, "xscale": 1.8, "yscale": 1.8, "zscale": 1.8}
blk.add_blockref('_ClosedBlank', (673.5, 243.46), dxfattribs=at)
at = {"color": 0, "lineweight": -2, "xscale": 1.8, "yscale": 1.8, "zscale": 1.8, "rotation": 180}
blk.add_blockref('_ClosedBlank', (675.5, 243.46), dxfattribs=at)
at = {"color": 0, "insert": (683.45, 243.46), "char_height": 1.8, "attachment_point": 5}
blk.add_mtext('\\A1;2.0mm', dxfattribs=at)
blk = doc.blocks.new('*D28')
at = {"color": 0, "lineweight": -2}
for p, q in [((507.12, 247.48), (515.03, 239.57)), ((504.43, 244.79), (512.34, 236.88)), ((515.03, 242.12), (516.31, 243.39)), ((516.31, 243.39), (518.11, 243.39)), ((509.8, 236.88), (508.52, 235.6))]:
    blk.add_line(p, q, dxfattribs=at)
at = {"layer": 'Defpoints', "color": 0}
for p in [(506.68, 247.92), (503.99, 245.23), (513.76, 240.84)]:
    blk.add_point(p, dxfattribs=at)
at = {"color": 0, "lineweight": -2, "xscale": 1.8, "yscale": 1.8, "zscale": 1.8}
for p, rotation in [((513.76, 240.84), 225.0000000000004), ((511.07, 238.15), 45.00000000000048)]:
    blk.add_blockref('_ClosedBlank', p, dxfattribs=dict(at, rotation=rotation))
at = {"color": 0, "insert": (523.21, 243.39), "char_height": 1.8, "attachment_point": 5}
blk.add_mtext('\\A1;\\S4.01mm^ 3.81mm;', dxfattribs=at)
blk = doc.blocks.new('*D29')
at = {"color": 0, "lineweight": -2}
for p, q in [((505.25, 252.05), (496.77, 260.53)), ((496.77, 257.99), (493.92, 255.15)), ((491.38, 252.6), (489.58, 252.6)), ((499.86, 246.66), (491.38, 255.15)), ((492.65, 253.87), (491.38, 252.6))]:
    blk.add_line(p, q, dxfattribs=at)
at = {"layer": 'Defpoints', "color": 0}
for p in [(492.65, 253.87), (505.69, 251.6), (500.31, 246.22)]:
    blk.add_point(p, dxfattribs=at)
at = {"color": 0, "lineweight": -2, "xscale": 1.8, "yscale": 1.8, "zscale": 1.8}
for p, rotation in [((498.04, 259.26), 45.00000000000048), ((492.65, 253.87), 225.0000000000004)]:
    blk.add_blockref('_ClosedBlank', p, dxfattribs=dict(at, rotation=rotation))
at = {"color": 0, "insert": (484.18, 252.6), "char_height": 1.8, "attachment_point": 5}
blk.add_mtext('\\A1;\\S7.68mm^ 7.62mm;', dxfattribs=at)
blk = doc.blocks.new('*D30')
at = {"color": 0, "lineweight": -2}
for p, q in [((499.04, 248.29), (499.04, 233.16)), ((506.96, 248.29), (506.96, 233.16)), ((499.04, 234.96), (497.24, 234.96)), ((505.16, 234.96), (500.84, 234.96))]:
    blk.add_line(p, q, dxfattribs=at)
at = {"layer": 'Defpoints', "color": 0}
for p in [(499.04, 248.91), (506.96, 248.91), (506.96, 234.96)]:
    blk.add_point(p, dxfattribs=at)
at = {"color": 0, "lineweight": -2, "xscale": 1.8, "yscale": 1.8, "zscale": 1.8, "rotation": 180}
blk.add_blockref('_ClosedBlank', (499.04, 234.96), dxfattribs=at)
at = {"color": 0, "lineweight": -2, "xscale": 1.8, "yscale": 1.8, "zscale": 1.8}
blk.add_blockref('_ClosedBlank', (506.96, 234.96), dxfattribs=at)
at = {"color": 0, "insert": (491.84, 234.96), "char_height": 1.8, "attachment_point": 5}
blk.add_mtext('\\A1;\\S8.12mm^ 7.92mm;', dxfattribs=at)

msp = doc.modelspace()

# ---------------------------------------------------------------- hatches: boundary and pattern name
at = {"layer": 'HATCH'}
h = msp.add_hatch(dxfattribs=at)
h.set_pattern_fill('ANSI31', color=256, scale=10, style=0)
h.set_pattern_definition([(45, (206.5568, 73.9106), (-0.8838835, 0.8838835), [])])
h.paths.add_polyline_path([(494.75002, 248.9106, 1), (511.25002, 248.9106, 1)])
h.paths.add_polyline_path([(506.68019, 249.89671), (506.82508, 249.93553, -0.131652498), (506.82508, 247.88568), (506.68019, 247.9245, -0.267949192), (503.98612, 245.23043), (504.02494, 245.08554, -0.131652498), (501.97509, 245.08554), (502.01392, 245.23043, -0.267949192), (499.31984, 247.9245), (499.17495, 247.88568, -0.131652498), (499.17495, 249.93553), (499.31984, 249.89671, -0.267949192), (502.01392, 252.59078), (501.97509, 252.73567, -0.131652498), (504.02494, 252.73567), (503.98612, 252.59078, -0.267949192)], flags=16)

# ---------------------------------------------------------------- linework, layer by layer
for p, q in [((502.01392, 252.59078), (501.97509, 252.73567)), ((503.98612, 252.59078), (504.02494, 252.73567)), ((499.31984, 249.89671), (499.17495, 249.93553)), ((506.68019, 249.89671), (506.82508, 249.93553)), ((499.31984, 247.9245), (499.17495, 247.88568)), ((506.68019, 247.9245), (506.82508, 247.88568)), ((502.01392, 245.23043), (501.97509, 245.08554)), ((503.98612, 245.23043), (504.02494, 245.08554)), ((440.86247, 229.1856), (443.6121, 233.9481)), ((539.80174, 228.6606), (542.55137, 233.4231)), ((422.38273, 228.49841), (422.46711, 229.1856)), ((422.46711, 229.1856), (458.47497, 229.1856)), ((422.46711, 208.6356), (422.46711, 229.1856)), ((439.48765, 231.56685), (440.86247, 229.1856)), ((458.92674, 228.73382), (458.47497, 229.1856)), ((458.47497, 208.6356), (458.47497, 229.1856)), ((458.92674, 209.08737), (458.92674, 228.73382)), ((538.42693, 231.04185), (539.80174, 228.6606)), ((646.25015, 228.81685), (647.62497, 226.4356)), ((647.62497, 226.4356), (650.3746, 231.1981)), ((459.10352, 228.6606), (620.49997, 228.6606)), ((459.10352, 209.1606), (459.10352, 228.6606)), ((620.49997, 209.1606), (620.49997, 228.6606)), ((620.99997, 209.6606), (620.99997, 228.1606)), ((621.24997, 226.4356), (673.49997, 226.4356)), ((621.24997, 211.3856), (621.24997, 226.4356)), ((673.49997, 211.3856), (673.49997, 226.4356)), ((675.60413, 225.11674), (675.99997, 225.80235)), ((675.99997, 225.80235), (676.12497, 225.80235)), ((676.12497, 225.80235), (676.5208, 225.11674)), ((676.60413, 225.11674), (676.99997, 225.80235)), ((676.99997, 225.80235), (677.12497, 225.80235)), ((677.12497, 225.80235), (677.5208, 225.11674)), ((677.60413, 225.11674), (677.99997, 225.80235)), ((677.99997, 225.80235), (678.12497, 225.80235)), ((678.12497, 225.80235), (678.5208, 225.11674)), ((678.60413, 225.11674), (678.99997, 225.80235)), ((678.99997, 225.80235), (679.12497, 225.80235)), ((679.12497, 225.80235), (679.5208, 225.11674)), ((679.60413, 225.11674), (679.99997, 225.80235)), ((679.99997, 225.80235), (680.12497, 225.80235)), ((680.12497, 225.80235), (680.5208, 225.11674)), ((680.60413, 225.11674), (680.99997, 225.80235)), ((680.99997, 225.80235), (681.12497, 225.80235)), ((681.12497, 225.80235), (681.5208, 225.11674)), ((681.60413, 225.11674), (681.99997, 225.80235)), ((681.99997, 225.80235), (682.12497, 225.80235)), ((682.12497, 225.80235), (682.5208, 225.11674)), ((682.60413, 225.11674), (682.99997, 225.80235)), ((682.99997, 225.80235), (683.12497, 225.80235)), ((683.12497, 225.80235), (683.5208, 225.11674)), ((683.60413, 225.11674), (683.99997, 225.80235)), ((683.99997, 225.80235), (684.12497, 225.80235)), ((684.12497, 225.80235), (684.5208, 225.11674)), ((684.60413, 225.11674), (684.99997, 225.80235)), ((684.99997, 225.80235), (685.12497, 225.80235)), ((685.12497, 225.80235), (685.5208, 225.11674)), ((685.60413, 225.11674), (685.99997, 225.80235)), ((685.99997, 225.80235), (686.12497, 225.80235)), ((686.12497, 225.80235), (686.5208, 225.11674)), ((686.60413, 225.11674), (686.99997, 225.80235)), ((686.99997, 225.80235), (687.12497, 225.80235)), ((687.12497, 225.80235), (687.5208, 225.11674)), ((687.60413, 225.11674), (687.99997, 225.80235)), ((687.99997, 225.80235), (688.12497, 225.80235)), ((688.12497, 225.80235), (688.5208, 225.11674)), ((688.60413, 225.11674), (688.99997, 225.80235)), ((688.99997, 225.80235), (689.12497, 225.80235)), ((689.12497, 225.80235), (689.5208, 225.11674)), ((689.60413, 225.11674), (689.99997, 225.80235)), ((689.99997, 225.80235), (690.12497, 225.80235)), ((690.12497, 225.80235), (690.5208, 225.11674)), ((690.60413, 225.11674), (690.99997, 225.80235)), ((690.99997, 225.80235), (691.12497, 225.80235)), ((691.12497, 225.80235), (691.5208, 225.11674)), ((691.60413, 225.11674), (691.99997, 225.80235)), ((691.99997, 212.66837), (691.99997, 225.80235)), ((691.99997, 225.80235), (691.99997, 212.66837)), ((673.49997, 224.9106), (675.49997, 224.9106)), ((675.49997, 212.01885), (675.49997, 225.15283)), ((675.49997, 225.15283), (675.5208, 225.11674)), ((675.60413, 225.11674), (675.5208, 225.11674)), ((676.49997, 225.15283), (676.5208, 225.11674)), ((676.5208, 225.11674), (676.60413, 225.11674)), ((676.60413, 225.11674), (676.5208, 225.11674)), ((677.49997, 225.15283), (677.5208, 225.11674)), ((677.5208, 225.11674), (677.60413, 225.11674)), ((677.60413, 225.11674), (677.5208, 225.11674)), ((678.49997, 225.15283), (678.5208, 225.11674)), ((678.5208, 225.11674), (678.60413, 225.11674)), ((678.60413, 225.11674), (678.5208, 225.11674)), ((679.5208, 225.11674), (679.60413, 225.11674)), ((679.60413, 225.11674), (679.5208, 225.11674)), ((680.60413, 225.11674), (680.5208, 225.11674)), ((681.60413, 225.11674), (681.5208, 225.11674)), ((682.60413, 225.11674), (682.5208, 225.11674)), ((683.60413, 225.11674), (683.5208, 225.11674)), ((684.60413, 225.11674), (684.5208, 225.11674)), ((685.60413, 225.11674), (685.5208, 225.11674)), ((686.60413, 225.11674), (686.5208, 225.11674)), ((687.60413, 225.11674), (687.5208, 225.11674)), ((688.60413, 225.11674), (688.5208, 225.11674)), ((689.60413, 225.11674), (689.5208, 225.11674)), ((690.60413, 225.11674), (690.5208, 225.11674)), ((691.60413, 225.11674), (691.5208, 225.11674)), ((621.24997, 211.3856), (673.49997, 211.3856)), ((673.49997, 212.9106), (675.49997, 212.9106)), ((675.49997, 212.01885), (675.62497, 212.01885)), ((675.62497, 212.01885), (676.0208, 212.70445)), ((676.0208, 212.70445), (676.10413, 212.70445)), ((676.10413, 212.70445), (676.0208, 212.70445)), ((676.10413, 212.70445), (676.49997, 212.01885)), ((676.49997, 212.01885), (676.62497, 212.01885)), ((676.62497, 212.01885), (677.0208, 212.70445)), ((677.0208, 212.70445), (677.10413, 212.70445)), ((677.10413, 212.70445), (677.0208, 212.70445)), ((677.10413, 212.70445), (677.49997, 212.01885)), ((677.49997, 212.01885), (677.62497, 212.01885)), ((677.62497, 212.01885), (678.0208, 212.70445)), ((678.0208, 212.70445), (678.10413, 212.70445)), ((678.10413, 212.70445), (678.0208, 212.70445)), ((678.10413, 212.70445), (678.49997, 212.01885)), ((678.49997, 212.01885), (678.62497, 212.01885)), ((678.62497, 212.01885), (679.0208, 212.70445)), ((679.0208, 212.70445), (679.10413, 212.70445)), ((679.10413, 212.70445), (679.0208, 212.70445)), ((679.10413, 212.70445), (679.49997, 212.01885)), ((679.49997, 212.01885), (679.62497, 212.01885)), ((679.62497, 212.01885), (680.0208, 212.70445)), ((680.10413, 212.70445), (680.0208, 212.70445)), ((680.10413, 212.70445), (680.49997, 212.01885)), ((680.49997, 212.01885), (680.62497, 212.01885)), ((680.62497, 212.01885), (681.0208, 212.70445)), ((681.10413, 212.70445), (681.0208, 212.70445)), ((681.10413, 212.70445), (681.49997, 212.01885)), ((681.49997, 212.01885), (681.62497, 212.01885)), ((681.62497, 212.01885), (682.0208, 212.70445)), ((682.10413, 212.70445), (682.0208, 212.70445)), ((682.10413, 212.70445), (682.49997, 212.01885)), ((682.49997, 212.01885), (682.62497, 212.01885)), ((682.62497, 212.01885), (683.0208, 212.70445)), ((683.10413, 212.70445), (683.0208, 212.70445)), ((683.10413, 212.70445), (683.49997, 212.01885)), ((683.49997, 212.01885), (683.62497, 212.01885)), ((683.62497, 212.01885), (684.0208, 212.70445)), ((684.10413, 212.70445), (684.0208, 212.70445)), ((684.10413, 212.70445), (684.49997, 212.01885)), ((684.49997, 212.01885), (684.62497, 212.01885)), ((684.62497, 212.01885), (685.0208, 212.70445)), ((685.10413, 212.70445), (685.0208, 212.70445)), ((685.10413, 212.70445), (685.49997, 212.01885)), ((685.49997, 212.01885), (685.62497, 212.01885)), ((685.62497, 212.01885), (686.0208, 212.70445)), ((686.10413, 212.70445), (686.0208, 212.70445)), ((686.10413, 212.70445), (686.49997, 212.01885)), ((686.49997, 212.01885), (686.62497, 212.01885)), ((686.62497, 212.01885), (687.0208, 212.70445)), ((687.10413, 212.70445), (687.0208, 212.70445)), ((687.10413, 212.70445), (687.49997, 212.01885)), ((687.49997, 212.01885), (687.62497, 212.01885)), ((687.62497, 212.01885), (688.0208, 212.70445)), ((688.10413, 212.70445), (688.0208, 212.70445)), ((688.10413, 212.70445), (688.49997, 212.01885)), ((688.49997, 212.01885), (688.62497, 212.01885)), ((688.62497, 212.01885), (689.0208, 212.70445)), ((689.10413, 212.70445), (689.0208, 212.70445)), ((689.10413, 212.70445), (689.49997, 212.01885)), ((689.49997, 212.01885), (689.62497, 212.01885)), ((689.62497, 212.01885), (690.0208, 212.70445)), ((690.10413, 212.70445), (690.0208, 212.70445)), ((690.10413, 212.70445), (690.49997, 212.01885)), ((690.49997, 212.01885), (690.62497, 212.01885)), ((690.62497, 212.01885), (691.0208, 212.70445)), ((691.10413, 212.70445), (691.0208, 212.70445)), ((691.10413, 212.70445), (691.49997, 212.01885)), ((691.49997, 212.01885), (691.62497, 212.01885)), ((691.62497, 212.01885), (691.99997, 212.66837)), ((422.38273, 209.32279), (422.46711, 208.6356)), ((422.46711, 208.6356), (458.47497, 208.6356)), ((458.92674, 209.08737), (458.47497, 208.6356)), ((459.10352, 209.1606), (620.49997, 209.1606))]:
    msp.add_line(p, q)
for points in [[(0, 0), (841, 0), (841, 594), (0, 594)], [(18.5, 20), (822.5, 20), (822.5, 574), (18.5, 574)]]:
    msp.add_lwpolyline(points, close=True)
msp.add_circle((503.00002, 248.9106), 8.25)
for centre, radius, start, end in [((503.00002, 248.9106), 3.81, 105, 165), ((503.00002, 248.9106), 3.96, 75, 105), ((503.00002, 248.9106), 3.81, 15, 75), ((503.00002, 248.9106), 3.96, 165, 195), ((503.00002, 248.9106), 3.96, 345, 15), ((503.00002, 248.9106), 3.81, 195, 255), ((503.00002, 248.9106), 3.81, 285, 345), ((503.00002, 248.9106), 3.96, 255, 285), ((459.10352, 228.9106), 0.25, 225, 270), ((620.49997, 228.1606), 0.5, 0, 90), ((621.24997, 226.6856), 0.25, 180, 270), ((621.24997, 211.1356), 0.25, 90, 180), ((459.10352, 208.9106), 0.25, 90, 135), ((620.49997, 209.6606), 0.5, 270, 0)]:
    msp.add_arc(centre, radius, start, end)
at = {"layer": 'CENTER'}
for p, q in [((503.00002, 245.4456), (503.00002, 252.3756)), ((499.53502, 248.9106), (506.46502, 248.9106))]:
    msp.add_line(p, q, dxfattribs=at)
at = {"layer": 'CENTERLINE'}
msp.add_line((146.29997, 218.9106), (694.49997, 218.9106), dxfattribs=at)
at = {"layer": 'HIDDEN'}
for p, q in [((184.5825, 222.873), (690.76572, 222.873)), ((184.7349, 222.7206), (689.99997, 222.7206)), ((689.99997, 215.1006), (689.99997, 222.7206)), ((689.99997, 222.7206), (689.99997, 215.1006)), ((184.58257, 214.9482), (690.76572, 214.9482)), ((184.73497, 215.1006), (689.99997, 215.1006))]:
    msp.add_line(p, q, dxfattribs=at)
for centre, start, end in [((689.99997, 224.7206), 270, 0), ((689.99997, 213.1006), 0, 90)]:
    msp.add_arc(centre, 2, start, end, dxfattribs=at)
at = {"layer": 'PHANTOM'}
msp.add_line((422.38273, 209.32279), (422.38273, 228.49841), dxfattribs=at)
at = {"layer": 'TEXT', "color": 7}
for p, q in [((428.41631, 167.48365), (428.41631, 170.48365)), ((428.41631, 170.48365), (433.41631, 170.48365)), ((433.41631, 170.48365), (438.41631, 170.48365)), ((433.41631, 167.48365), (433.41631, 170.48365)), ((438.41631, 170.48365), (446.41631, 170.48365)), ((438.41631, 167.48365), (438.41631, 170.48365)), ((446.41631, 167.48365), (446.41631, 170.48365)), ((428.41631, 167.48365), (433.41631, 167.48365)), ((433.41631, 167.48365), (438.41631, 167.48365)), ((438.41631, 167.48365), (446.41631, 167.48365)), ((639.05958, 165.91057), (639.05958, 168.91057)), ((639.05958, 168.91057), (644.05958, 168.91057)), ((644.05958, 168.91057), (649.05958, 168.91057)), ((644.05958, 165.91057), (644.05958, 168.91057)), ((649.05958, 168.91057), (657.05958, 168.91057)), ((649.05958, 165.91057), (649.05958, 168.91057)), ((657.05958, 165.91057), (657.05958, 168.91057)), ((639.05958, 165.91057), (644.05958, 165.91057)), ((644.05958, 165.91057), (649.05958, 165.91057)), ((649.05958, 165.91057), (657.05958, 165.91057))]:
    msp.add_line(p, q, dxfattribs=at)
for centre, radius in [((430.91631, 168.98365), 1.25), ((430.91631, 168.98365), 0.75), ((641.55958, 167.41057), 1.25), ((641.55958, 167.41057), 0.75)]:
    msp.add_circle(centre, radius, dxfattribs=at)

# ---------------------------------------------------------------- texts
for s, p in [('N6', (440.86247, 231.56685)), ('N8', (539.80174, 231.04185)), ('N6', (647.62497, 228.81685))]:
    msp.add_text(s, height=1.5875).set_placement(p, align=Align.BOTTOM_CENTER)
at = {"char_height": 2, "width": 10.5482646, "attachment_point": 2}
for s, insert in [('\\A1;%%C12,0mm', (674.49997, 195.9106)), ('\\A1;%%C19,5mm', (539.80174, 192.1606))]:
    msp.add_mtext(s, dxfattribs=dict(at, insert=insert))
at = {"layer": 'TEXT', "color": 7}
for s, insert, char_height, width, attachment_point in [('\\A1;{\\H0.75x;M14 X 1,0 LH\\PMajor %%C\\H0.7x;\\S14,000mm/13,988mm;\\H1.429x;\\PPitch %%C\\H0.7x;\\S13,350mm/13,240mm;\\H1.429x;\\PRoot} {\\H0.75x;%%C\\H0.7x;12,701mm}', (682.45201, 203.28151), 2, 19.3860592, 1), ('\\A1;Size 1 %%C20,518mm/%%C20,533mm\\P{\\LSize 2 %%C20,548mm/%%C20,563mm}\\PSize 3 %%C20,563mm/%%C20,578mm\\PSize 4 %%C20,618mm/%%C20,638mm', (416.30845, 183.96663), 2, 48.5376086, 1), ('\\A1;Size 1 %%C15,018mm/%%C15,033mm\\P{\\LSize 2 %%C15,048mm/%%C15,063mm}\\PSize 3 %%C15,063mm/%%C15,078mm\\PSize 4 %%C15,118mm/%%C15,138mm', (625.66815, 181.91057), 2, 48.5376086, 1), ('-A-', (435.91631, 168.98365), 1.5, 1.19634, 5), ('0,02mm', (442.41631, 168.98365), 1.5, 6.6720954, 5), ('-A-', (646.55958, 167.41057), 1.5, 1.19634, 5), ('0,01mm', (653.05958, 167.41057), 1.5, 6.6720954, 5)]:
    msp.add_mtext(s, dxfattribs=dict(at, insert=insert, char_height=char_height, width=width, attachment_point=attachment_point))

# ---------------------------------------------------------------- dimensions: what is measured, and where the dimension line sits
for base, p1, p2, picture, middle in [((691.99997, 275.46019), (149.99997, 229.83168), (691.99997, 225.80235), '*D15', (420.99997, 275.46019)), ((149.99997, 271.46165), (620.99997, 228.1606), (149.99997, 229.83168), '*D13', (385.49997, 271.46165)), ((149.99997, 267.46311), (458.47497, 229.1856), (149.99997, 229.83168), '*D12', (304.23747, 267.46311)), ((675.49997, 243.46019), (673.49997, 226.4356), (675.49997, 225.15283), '*D17', (683.44997, 243.46019))]:
    dim = msp.add_linear_dim(base=base, p1=p1, p2=p2, dimstyle='Standard$0', override={"dimscale": 10, "dimdec": 1, "dimpost": 'mm', "dimblk1": 'ClosedBlank', "dimblk2": 'ClosedBlank', "dimsah": 1})
    dim.commit()
    dim.dimension.update_dxf_attribs({"geometry": picture, "text_midpoint": middle})
for base, p1, p2, angle, override, picture, middle in [((492.64971, 253.87276), (505.69409, 251.60468), (500.30594, 246.21653), 225, {"dimgap": 0.09, "dimpost": 'mm', "dimtol": 0, "dimlim": 1, "dimtp": 0.06, "dimtm": 1e-09, "dimtdec": 2}, '*D29', (484.17692, 252.59996)), ((513.762, 240.8427), (503.98612, 245.23043), (506.68019, 247.9245), 45, {"dimgap": 0.09, "dimpost": 'mm', "dimtol": 0, "dimlim": 1, "dimtp": 0.2, "dimtm": 1e-09, "dimtdec": 2}, '*D28', (523.20758, 243.38829))]:
    dim = msp.add_linear_dim(base=base, p1=p1, p2=p2, angle=angle, dimstyle='Standard$0', override=override)
    dim.commit()
    dim.dimension.update_dxf_attribs({"geometry": picture, "text_midpoint": middle})
for base, p1, p2, override, picture, middle in [((673.49997, 248.83098), (691.99997, 225.80235), (673.49997, 230.43852), {"dimscale": 10, "dimdec": 1, "dimpost": 'mm', "dimblk1": 'ClosedBlank', "dimblk2": 'ClosedBlank', "dimsah": 1}, '*D14', (682.74997, 248.83098)), ((506.96002, 234.96278), (499.04002, 248.9106), (506.96002, 248.9106), {"dimgap": 0.09, "dimpost": 'mm', "dimtol": 0, "dimlim": 1, "dimtp": 0.2, "dimtm": 1e-09, "dimtdec": 2}, '*D30', (491.84002, 234.96278))]:
    dim = msp.add_linear_dim(base=base, p1=p1, p2=p2, dimstyle='Standard$0', override=override)
    dim.commit()
    dim.dimension.update_dxf_attribs({"geometry": picture, "text_midpoint": middle, "dimtype": 160})

# ---------------------------------------------------------------- leaders
for points in [[(674.49997, 212.9106), (674.49997, 195.9106)], [(689.56247, 212.01885), (689.56247, 204.36985)], [(539.80174, 209.1606), (539.80174, 192.1606)]]:
    msp.add_leader(points, dimstyle='Standard', override={"dimscale": 1, "dimasz": 2, "dimgap": 0.09, "dimtad": 0, "dimldrblk": 'ClosedBlank'})
for points in [[(647.62497, 211.3856), (647.62497, 183.14958)], [(440.86247, 208.6356), (440.86247, 184.40958)]]:
    msp.add_leader(points, dimstyle='Standard', override={"dimscale": 1, "dimasz": 2, "dimgap": 0.09, "dimtad": 0, "dimldrblk": 'ClosedBlank'}, dxfattribs=at)

doc.saveas('drawing.dxf')
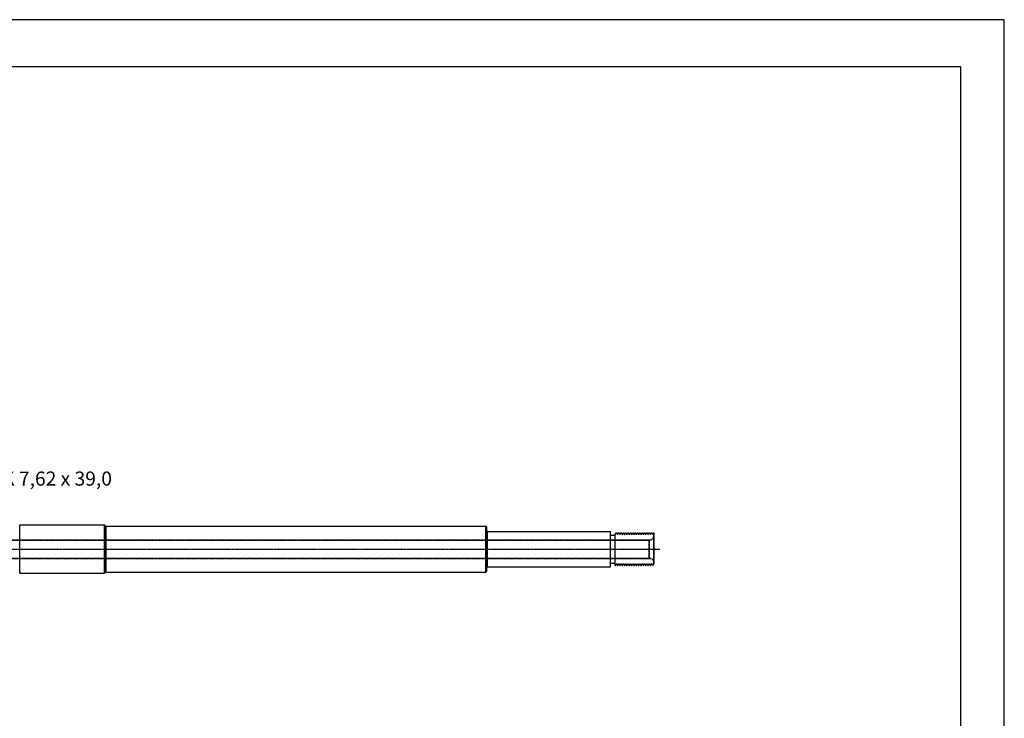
# Model space of a CAD drawing. Units: inches. Extents: x 0 to 841, y 0 to 594.
# Drawn here: x 422 to 841, y 297 to 594 of the extents above; entities that cross this region are included whole.
import ezdxf
from ezdxf.enums import TextEntityAlignment as Align

# ---------------------------------------------------------------- set-up
doc = ezdxf.new("R2010")
doc.units = ezdxf.units.IN
doc.header["$MEASUREMENT"] = 0
for name, pattern in [('CENTER2', [1.125, 0.75, -0.125, 0.125, -0.125]), ('HIDDEN2', [0.1875, 0.125, -0.0625]), ('PHANTOM', [2.5, 1.25, -0.25, 0.25, -0.25, 0.25, -0.25])]:
    doc.linetypes.add(name, pattern=pattern)
for name, color, linetype in [('CENTERLINE', 1, 'CENTER2'), ('HIDDEN', 5, 'HIDDEN2'), ('PHANTOM', 252, 'PHANTOM')]:
    doc.layers.add(name, color=color, linetype=linetype)

msp = doc.modelspace()

# ---------------------------------------------------------------- linework, layer by layer
for p, q in [((422.38273, 378.49841), (422.46711, 379.1856)), ((422.46711, 379.1856), (458.47497, 379.1856)), ((422.46711, 358.6356), (422.46711, 379.1856)), ((458.92674, 378.73382), (458.47497, 379.1856)), ((458.47497, 358.6356), (458.47497, 379.1856)), ((458.92674, 359.08737), (458.92674, 378.73382)), ((459.10352, 378.6606), (620.49997, 378.6606)), ((459.10352, 359.1606), (459.10352, 378.6606)), ((620.49997, 359.1606), (620.49997, 378.6606)), ((620.99997, 359.6606), (620.99997, 378.1606)), ((621.24997, 376.4356), (673.49997, 376.4356)), ((621.24997, 361.3856), (621.24997, 376.4356)), ((673.49997, 361.3856), (673.49997, 376.4356)), ((673.49997, 374.9106), (675.49997, 374.9106)), ((675.49997, 362.01885), (675.49997, 375.15283)), ((675.49997, 375.15283), (675.5208, 375.11674)), ((675.60413, 375.11674), (675.5208, 375.11674)), ((675.60413, 375.11674), (675.99997, 375.80235)), ((675.99997, 375.80235), (676.12497, 375.80235)), ((676.12497, 375.80235), (676.5208, 375.11674)), ((676.49997, 375.15283), (676.5208, 375.11674)), ((676.5208, 375.11674), (676.60413, 375.11674)), ((676.60413, 375.11674), (676.5208, 375.11674)), ((676.60413, 375.11674), (676.99997, 375.80235)), ((676.99997, 375.80235), (677.12497, 375.80235)), ((677.12497, 375.80235), (677.5208, 375.11674)), ((677.49997, 375.15283), (677.5208, 375.11674)), ((677.5208, 375.11674), (677.60413, 375.11674)), ((677.60413, 375.11674), (677.5208, 375.11674)), ((677.60413, 375.11674), (677.99997, 375.80235)), ((677.99997, 375.80235), (678.12497, 375.80235)), ((678.12497, 375.80235), (678.5208, 375.11674)), ((678.49997, 375.15283), (678.5208, 375.11674)), ((678.5208, 375.11674), (678.60413, 375.11674)), ((678.60413, 375.11674), (678.5208, 375.11674)), ((678.60413, 375.11674), (678.99997, 375.80235)), ((678.99997, 375.80235), (679.12497, 375.80235)), ((679.12497, 375.80235), (679.5208, 375.11674)), ((679.5208, 375.11674), (679.60413, 375.11674)), ((679.60413, 375.11674), (679.5208, 375.11674)), ((679.60413, 375.11674), (679.99997, 375.80235)), ((679.99997, 375.80235), (680.12497, 375.80235)), ((680.12497, 375.80235), (680.5208, 375.11674)), ((680.60413, 375.11674), (680.5208, 375.11674)), ((680.60413, 375.11674), (680.99997, 375.80235)), ((680.99997, 375.80235), (681.12497, 375.80235)), ((681.12497, 375.80235), (681.5208, 375.11674)), ((681.60413, 375.11674), (681.5208, 375.11674)), ((681.60413, 375.11674), (681.99997, 375.80235)), ((681.99997, 375.80235), (682.12497, 375.80235)), ((682.12497, 375.80235), (682.5208, 375.11674)), ((682.60413, 375.11674), (682.5208, 375.11674)), ((682.60413, 375.11674), (682.99997, 375.80235)), ((682.99997, 375.80235), (683.12497, 375.80235)), ((683.12497, 375.80235), (683.5208, 375.11674)), ((683.60413, 375.11674), (683.5208, 375.11674)), ((683.60413, 375.11674), (683.99997, 375.80235)), ((683.99997, 375.80235), (684.12497, 375.80235)), ((684.12497, 375.80235), (684.5208, 375.11674)), ((684.60413, 375.11674), (684.5208, 375.11674)), ((684.60413, 375.11674), (684.99997, 375.80235)), ((684.99997, 375.80235), (685.12497, 375.80235)), ((685.12497, 375.80235), (685.5208, 375.11674)), ((685.60413, 375.11674), (685.5208, 375.11674)), ((685.60413, 375.11674), (685.99997, 375.80235)), ((685.99997, 375.80235), (686.12497, 375.80235)), ((686.12497, 375.80235), (686.5208, 375.11674)), ((686.60413, 375.11674), (686.5208, 375.11674)), ((686.60413, 375.11674), (686.99997, 375.80235)), ((686.99997, 375.80235), (687.12497, 375.80235)), ((687.12497, 375.80235), (687.5208, 375.11674)), ((687.60413, 375.11674), (687.5208, 375.11674)), ((687.60413, 375.11674), (687.99997, 375.80235)), ((687.99997, 375.80235), (688.12497, 375.80235)), ((688.12497, 375.80235), (688.5208, 375.11674)), ((688.60413, 375.11674), (688.5208, 375.11674)), ((688.60413, 375.11674), (688.99997, 375.80235)), ((688.99997, 375.80235), (689.12497, 375.80235)), ((689.12497, 375.80235), (689.5208, 375.11674)), ((689.60413, 375.11674), (689.5208, 375.11674)), ((689.60413, 375.11674), (689.99997, 375.80235)), ((689.99997, 375.80235), (690.12497, 375.80235)), ((690.12497, 375.80235), (690.5208, 375.11674)), ((690.60413, 375.11674), (690.5208, 375.11674)), ((690.60413, 375.11674), (690.99997, 375.80235)), ((690.99997, 375.80235), (691.12497, 375.80235)), ((691.12497, 375.80235), (691.5208, 375.11674)), ((691.60413, 375.11674), (691.5208, 375.11674)), ((691.60413, 375.11674), (691.99997, 375.80235)), ((691.99997, 362.66837), (691.99997, 375.80235)), ((691.99997, 375.80235), (691.99997, 362.66837)), ((621.24997, 361.3856), (673.49997, 361.3856)), ((673.49997, 362.9106), (675.49997, 362.9106)), ((675.49997, 362.01885), (675.62497, 362.01885)), ((675.62497, 362.01885), (676.0208, 362.70445)), ((676.0208, 362.70445), (676.10413, 362.70445)), ((676.10413, 362.70445), (676.0208, 362.70445)), ((676.10413, 362.70445), (676.49997, 362.01885)), ((676.49997, 362.01885), (676.62497, 362.01885)), ((676.62497, 362.01885), (677.0208, 362.70445)), ((677.0208, 362.70445), (677.10413, 362.70445)), ((677.10413, 362.70445), (677.0208, 362.70445)), ((677.10413, 362.70445), (677.49997, 362.01885)), ((677.49997, 362.01885), (677.62497, 362.01885)), ((677.62497, 362.01885), (678.0208, 362.70445)), ((678.0208, 362.70445), (678.10413, 362.70445)), ((678.10413, 362.70445), (678.0208, 362.70445)), ((678.10413, 362.70445), (678.49997, 362.01885)), ((678.49997, 362.01885), (678.62497, 362.01885)), ((678.62497, 362.01885), (679.0208, 362.70445)), ((679.0208, 362.70445), (679.10413, 362.70445)), ((679.10413, 362.70445), (679.0208, 362.70445)), ((679.10413, 362.70445), (679.49997, 362.01885)), ((679.49997, 362.01885), (679.62497, 362.01885)), ((679.62497, 362.01885), (680.0208, 362.70445)), ((680.10413, 362.70445), (680.0208, 362.70445)), ((680.10413, 362.70445), (680.49997, 362.01885)), ((680.49997, 362.01885), (680.62497, 362.01885)), ((680.62497, 362.01885), (681.0208, 362.70445)), ((681.10413, 362.70445), (681.0208, 362.70445)), ((681.10413, 362.70445), (681.49997, 362.01885)), ((681.49997, 362.01885), (681.62497, 362.01885)), ((681.62497, 362.01885), (682.0208, 362.70445)), ((682.10413, 362.70445), (682.0208, 362.70445)), ((682.10413, 362.70445), (682.49997, 362.01885)), ((682.49997, 362.01885), (682.62497, 362.01885)), ((682.62497, 362.01885), (683.0208, 362.70445)), ((683.10413, 362.70445), (683.0208, 362.70445)), ((683.10413, 362.70445), (683.49997, 362.01885)), ((683.49997, 362.01885), (683.62497, 362.01885)), ((683.62497, 362.01885), (684.0208, 362.70445)), ((684.10413, 362.70445), (684.0208, 362.70445)), ((684.10413, 362.70445), (684.49997, 362.01885)), ((684.49997, 362.01885), (684.62497, 362.01885)), ((684.62497, 362.01885), (685.0208, 362.70445)), ((685.10413, 362.70445), (685.0208, 362.70445)), ((685.10413, 362.70445), (685.49997, 362.01885)), ((685.49997, 362.01885), (685.62497, 362.01885)), ((685.62497, 362.01885), (686.0208, 362.70445)), ((686.10413, 362.70445), (686.0208, 362.70445)), ((686.10413, 362.70445), (686.49997, 362.01885)), ((686.49997, 362.01885), (686.62497, 362.01885)), ((686.62497, 362.01885), (687.0208, 362.70445)), ((687.10413, 362.70445), (687.0208, 362.70445)), ((687.10413, 362.70445), (687.49997, 362.01885)), ((687.49997, 362.01885), (687.62497, 362.01885)), ((687.62497, 362.01885), (688.0208, 362.70445)), ((688.10413, 362.70445), (688.0208, 362.70445)), ((688.10413, 362.70445), (688.49997, 362.01885)), ((688.49997, 362.01885), (688.62497, 362.01885)), ((688.62497, 362.01885), (689.0208, 362.70445)), ((689.10413, 362.70445), (689.0208, 362.70445)), ((689.10413, 362.70445), (689.49997, 362.01885)), ((689.49997, 362.01885), (689.62497, 362.01885)), ((689.62497, 362.01885), (690.0208, 362.70445)), ((690.10413, 362.70445), (690.0208, 362.70445)), ((690.10413, 362.70445), (690.49997, 362.01885)), ((690.49997, 362.01885), (690.62497, 362.01885)), ((690.62497, 362.01885), (691.0208, 362.70445)), ((691.10413, 362.70445), (691.0208, 362.70445)), ((691.10413, 362.70445), (691.49997, 362.01885)), ((691.49997, 362.01885), (691.62497, 362.01885)), ((691.62497, 362.01885), (691.99997, 362.66837)), ((422.38273, 359.32279), (422.46711, 358.6356)), ((422.46711, 358.6356), (458.47497, 358.6356)), ((458.92674, 359.08737), (458.47497, 358.6356)), ((459.10352, 359.1606), (620.49997, 359.1606))]:
    msp.add_line(p, q)
for points in [[(0, 0), (841, 0), (841, 594), (0, 594)], [(18.5, 20), (822.5, 20), (822.5, 574), (18.5, 574)]]:
    msp.add_lwpolyline(points, close=True)
for centre, radius, start, end in [((459.10352, 378.9106), 0.25, 225, 270), ((620.49997, 378.1606), 0.5, 0, 90), ((621.24997, 376.6856), 0.25, 180, 270), ((621.24997, 361.1356), 0.25, 90, 180), ((459.10352, 358.9106), 0.25, 90, 135), ((620.49997, 359.6606), 0.5, 270, 0)]:
    msp.add_arc(centre, radius, start, end)
at = {"layer": 'CENTERLINE'}
msp.add_line((146.99997, 368.9106), (694.49997, 368.9106), dxfattribs=at)
at = {"layer": 'HIDDEN'}
for p, q in [((184.5825, 372.873), (690.76572, 372.873)), ((184.7349, 372.7206), (689.99997, 372.7206)), ((689.99997, 365.1006), (689.99997, 372.7206)), ((689.99997, 372.7206), (689.99997, 365.1006)), ((184.58257, 364.9482), (690.76572, 364.9482)), ((184.73497, 365.1006), (689.99997, 365.1006))]:
    msp.add_line(p, q, dxfattribs=at)
for centre, start, end in [((689.99997, 374.7206), 270, 0), ((689.99997, 363.1006), 0, 90)]:
    msp.add_arc(centre, 2, start, end, dxfattribs=at)
at = {"layer": 'PHANTOM'}
msp.add_line((422.38273, 359.32279), (422.38273, 378.49841), dxfattribs=at)

# ---------------------------------------------------------------- texts
msp.add_text('Yugoslavian M72 RPK 7,62 x 39,0', height=6).set_placement((400.5, 398.91057), align=Align.MIDDLE_CENTER)

doc.saveas('drawing.dxf')
